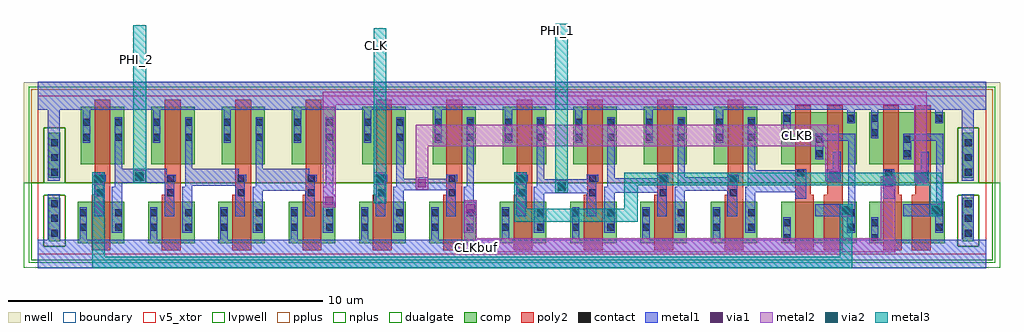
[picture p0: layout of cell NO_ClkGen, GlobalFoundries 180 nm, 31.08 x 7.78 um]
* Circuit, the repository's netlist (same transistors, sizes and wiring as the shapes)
* NGSPICE file created from NO_ClkGen.ext - technology: gf180mcuD

.subckt gf180mcu_fd_sc_mcu9t5v0__nand2_1 ZN VSS VDD A2 A1 VNW VPW
X0 ZN A2 VDD VNW pfet_05v0 ad=0.4277p pd=2.165u as=0.7238p ps=4.17u w=1.645u l=0.5u
X1 VDD A1 ZN VNW pfet_05v0 ad=0.7238p pd=4.17u as=0.4277p ps=2.165u w=1.645u l=0.5u
X2 ZN A1 a_245_69# VPW nfet_05v0 ad=0.5808p pd=3.52u as=0.2112p ps=1.64u w=1.32u l=0.6u
X3 a_245_69# A2 VSS VPW nfet_05v0 ad=0.2112p pd=1.64u as=0.5808p ps=3.52u w=1.32u l=0.6u
.ends

.subckt gf180mcu_fd_sc_mcu9t5v0__inv_1 I VDD VSS ZN VNW VPW
X0 ZN I VDD VNW pfet_05v0 ad=0.8052p pd=4.54u as=0.8052p ps=4.54u w=1.83u l=0.5u
X1 ZN I VSS VPW nfet_05v0 ad=0.5808p pd=3.52u as=0.5808p ps=3.52u w=1.32u l=0.6u
.ends

.subckt NO_ClkGen CLKB CLKbuf PHI_2 PHI_1 CLK
Xgf180mcu_fd_sc_mcu9t5v0__nand2_1_0 gf180mcu_fd_sc_mcu9t5v0__inv_1_1/I VSUBS gf180mcu_fd_sc_mcu9t5v0__inv_1_9/VNW
+ gf180mcu_fd_sc_mcu9t5v0__inv_1_0/ZN CLKB gf180mcu_fd_sc_mcu9t5v0__inv_1_9/VNW VSUBS
+ gf180mcu_fd_sc_mcu9t5v0__nand2_1
Xgf180mcu_fd_sc_mcu9t5v0__nand2_1_1 gf180mcu_fd_sc_mcu9t5v0__inv_1_7/I VSUBS gf180mcu_fd_sc_mcu9t5v0__inv_1_9/VNW
+ CLKbuf gf180mcu_fd_sc_mcu9t5v0__inv_1_4/ZN gf180mcu_fd_sc_mcu9t5v0__inv_1_9/VNW
+ VSUBS gf180mcu_fd_sc_mcu9t5v0__nand2_1
Xgf180mcu_fd_sc_mcu9t5v0__inv_1_0 gf180mcu_fd_sc_mcu9t5v0__inv_1_0/I gf180mcu_fd_sc_mcu9t5v0__inv_1_9/VNW
+ VSUBS gf180mcu_fd_sc_mcu9t5v0__inv_1_0/ZN gf180mcu_fd_sc_mcu9t5v0__inv_1_9/VNW VSUBS
+ gf180mcu_fd_sc_mcu9t5v0__inv_1
Xgf180mcu_fd_sc_mcu9t5v0__inv_1_1 gf180mcu_fd_sc_mcu9t5v0__inv_1_1/I gf180mcu_fd_sc_mcu9t5v0__inv_1_9/VNW
+ VSUBS PHI_2 gf180mcu_fd_sc_mcu9t5v0__inv_1_9/VNW VSUBS gf180mcu_fd_sc_mcu9t5v0__inv_1
Xgf180mcu_fd_sc_mcu9t5v0__inv_1_2 PHI_2 gf180mcu_fd_sc_mcu9t5v0__inv_1_9/VNW VSUBS
+ gf180mcu_fd_sc_mcu9t5v0__inv_1_3/I gf180mcu_fd_sc_mcu9t5v0__inv_1_9/VNW VSUBS gf180mcu_fd_sc_mcu9t5v0__inv_1
Xgf180mcu_fd_sc_mcu9t5v0__inv_1_3 gf180mcu_fd_sc_mcu9t5v0__inv_1_3/I gf180mcu_fd_sc_mcu9t5v0__inv_1_9/VNW
+ VSUBS gf180mcu_fd_sc_mcu9t5v0__inv_1_4/I gf180mcu_fd_sc_mcu9t5v0__inv_1_9/VNW VSUBS
+ gf180mcu_fd_sc_mcu9t5v0__inv_1
Xgf180mcu_fd_sc_mcu9t5v0__inv_1_4 gf180mcu_fd_sc_mcu9t5v0__inv_1_4/I gf180mcu_fd_sc_mcu9t5v0__inv_1_9/VNW
+ VSUBS gf180mcu_fd_sc_mcu9t5v0__inv_1_4/ZN gf180mcu_fd_sc_mcu9t5v0__inv_1_9/VNW VSUBS
+ gf180mcu_fd_sc_mcu9t5v0__inv_1
Xgf180mcu_fd_sc_mcu9t5v0__inv_1_5 CLK gf180mcu_fd_sc_mcu9t5v0__inv_1_9/VNW VSUBS CLKB
+ gf180mcu_fd_sc_mcu9t5v0__inv_1_9/VNW VSUBS gf180mcu_fd_sc_mcu9t5v0__inv_1
Xgf180mcu_fd_sc_mcu9t5v0__inv_1_6 CLKB gf180mcu_fd_sc_mcu9t5v0__inv_1_9/VNW VSUBS
+ CLKbuf gf180mcu_fd_sc_mcu9t5v0__inv_1_9/VNW VSUBS gf180mcu_fd_sc_mcu9t5v0__inv_1
Xgf180mcu_fd_sc_mcu9t5v0__inv_1_7 gf180mcu_fd_sc_mcu9t5v0__inv_1_7/I gf180mcu_fd_sc_mcu9t5v0__inv_1_9/VNW
+ VSUBS PHI_1 gf180mcu_fd_sc_mcu9t5v0__inv_1_9/VNW VSUBS gf180mcu_fd_sc_mcu9t5v0__inv_1
Xgf180mcu_fd_sc_mcu9t5v0__inv_1_8 PHI_1 gf180mcu_fd_sc_mcu9t5v0__inv_1_9/VNW VSUBS
+ gf180mcu_fd_sc_mcu9t5v0__inv_1_9/I gf180mcu_fd_sc_mcu9t5v0__inv_1_9/VNW VSUBS gf180mcu_fd_sc_mcu9t5v0__inv_1
Xgf180mcu_fd_sc_mcu9t5v0__inv_1_9 gf180mcu_fd_sc_mcu9t5v0__inv_1_9/I gf180mcu_fd_sc_mcu9t5v0__inv_1_9/VNW
+ VSUBS gf180mcu_fd_sc_mcu9t5v0__inv_1_0/I gf180mcu_fd_sc_mcu9t5v0__inv_1_9/VNW VSUBS
+ gf180mcu_fd_sc_mcu9t5v0__inv_1
.ends

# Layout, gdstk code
import gdstk
lib = gdstk.Library(unit=1e-6, precision=1e-09)
def R(c, l, rs):  # rectangles x0, y0, x1, y1
    for r in rs: c.add(gdstk.rectangle(r[:2], r[2:], *l))
def A(c, l, x, y, w, h, nx, ny, dx, dy):  # array of equal rectangles
    R(c, l, [(x+i*dx, y+j*dy, x+i*dx+w, y+j*dy+h) for i in range(nx) for j in range(ny)])
def P(c, l, *ps):  # polygons
    for p in ps: c.add(gdstk.Polygon(p, *l))
boundary = (0, 0)
nwell = (21, 0)
comp = (22, 0)
poly2 = (30, 0)
pplus = (31, 0)
nplus = (32, 0)
contact = (33, 0)
metal1 = (34, 0)
via1 = (35, 0)
metal2 = (36, 0)
via2 = (38, 0)
metal3 = (42, 0)
dualgate = (55, 0)
v5_xtor = (112, 1)
lvpwell = (204, 0)

gf180mcu_fd_sc_mcu9t5v0_ = lib.new_cell('gf180mcu_fd_sc_mcu9t5v0__inv_1')
R(gf180mcu_fd_sc_mcu9t5v0_, boundary, [(0,0,2.24,5.04)])
R(gf180mcu_fd_sc_mcu9t5v0_, nwell, [(-0.43,2.265,2.67,5.47)])
R(gf180mcu_fd_sc_mcu9t5v0_, comp, [(0.18,0.345,1.66,1.665), (0.28,2.865,1.66,4.695)])
P(gf180mcu_fd_sc_mcu9t5v0_, poly2, [(0.62,0.125),(0.62,1.885),(0.72,1.885),(0.72,4.915),(1.22,4.915),(1.22,0.125)])
R(gf180mcu_fd_sc_mcu9t5v0_, pplus, [(-0.2,2.265,2.44,5.24)])
R(gf180mcu_fd_sc_mcu9t5v0_, nplus, [(-0.2,-0.2,2.44,2.265)])
R(gf180mcu_fd_sc_mcu9t5v0_, contact, [(0.25,0.74,0.47,0.96), (1.37,0.74,1.59,0.96), (0.25,1.21,0.47,1.43), (1.37,1.21,1.59,1.43), (0.79,1.835,1.01,2.055), (0.79,2.305,1.01,2.525), (0.35,3.61,0.57,3.83), (1.37,3.61,1.59,3.83), (0.35,4.08,0.57,4.3), (1.37,4.08,1.59,4.3)])
P(gf180mcu_fd_sc_mcu9t5v0_, metal1, [(0.71,1.21),(0.71,2.53),(1.07,2.53),(1.07,2.3),(1.015,2.3),(1.015,1.21)],
  [(1.27,0.68),(1.27,2.15),(1.365,2.15),(1.365,4.36),(1.595,4.36),(1.595,0.68)],
  [(0,-0.45),(0,0.45),(0.245,0.45),(0.245,1.49),(0.475,1.49),(0.475,0.45),(2.24,0.45),(2.24,-0.45)],
  [(0.345,3.55),(0.345,4.59),(0,4.59),(0,5.49),(2.24,5.49),(2.24,4.59),(0.575,4.59),(0.575,3.55)])
R(gf180mcu_fd_sc_mcu9t5v0_, dualgate, [(-0.28,-0.28,2.52,5.32)])
R(gf180mcu_fd_sc_mcu9t5v0_, v5_xtor, [(0,0,2.24,5.04)])
R(gf180mcu_fd_sc_mcu9t5v0_, lvpwell, [(-0.43,-0.43,2.67,2.265)])
gf180mcu_fd_sc_mcu9t5v0_.add(gdstk.Label('& Vendor GLOBALFOUNDRIES', (0,2), layer=63, texttype=63))
gf180mcu_fd_sc_mcu9t5v0_.add(gdstk.Label('& Product GF018hv5v_green_sc9', (0,1.5), layer=63, texttype=63))
gf180mcu_fd_sc_mcu9t5v0_.add(gdstk.Label('& Version 2015q2v2', (0,1), layer=63, texttype=63))
gf180mcu_fd_sc_mcu9t5v0_.add(gdstk.Label('& Metric 1.00', (0,0.5), layer=63, texttype=63))
gf180mcu_fd_sc_mcu9t5v0_.add(gdstk.Label('I', (0.84,1.96), layer=34, texttype=10))
gf180mcu_fd_sc_mcu9t5v0_.add(gdstk.Label('VDD', (1.12,5.49), layer=34, texttype=10))
gf180mcu_fd_sc_mcu9t5v0_.add(gdstk.Label('VSS', (1.12,-0.45), layer=34, texttype=10))
gf180mcu_fd_sc_mcu9t5v0_.add(gdstk.Label('ZN', (1.4,1.96), layer=34, texttype=10))
gf180mcu_fd_sc_mcu9t5v0_.add(gdstk.Label('VNW', (0.345,3.92), layer=21, texttype=10))
gf180mcu_fd_sc_mcu9t5v0_.add(gdstk.Label('VPW', (0.34,-0.085), layer=204, texttype=10))

c_gf180mcu_fd_sc_mcu9t5v0_ = lib.new_cell('gf180mcu_fd_sc_mcu9t5v0__nand2_1')
R(c_gf180mcu_fd_sc_mcu9t5v0_, boundary, [(0,0,2.8,5.04)])
R(c_gf180mcu_fd_sc_mcu9t5v0_, nwell, [(-0.43,2.265,3.23,5.47)])
R(c_gf180mcu_fd_sc_mcu9t5v0_, comp, [(0.185,0.345,2.585,1.665), (0.185,2.865,2.585,4.51)])
P(c_gf180mcu_fd_sc_mcu9t5v0_, poly2, [(0.625,0.125),(0.625,4.73),(1.125,4.73),(1.125,1.885),(1.225,1.885),(1.225,0.125)],
  [(1.545,0.125),(1.545,1.885),(1.645,1.885),(1.645,4.73),(2.145,4.73),(2.145,0.125)])
R(c_gf180mcu_fd_sc_mcu9t5v0_, pplus, [(-0.2,2.265,3,5.24)])
R(c_gf180mcu_fd_sc_mcu9t5v0_, nplus, [(-0.2,-0.2,3,2.265)])
R(c_gf180mcu_fd_sc_mcu9t5v0_, contact, [(0.255,0.415,0.475,0.635), (2.295,0.74,2.515,0.96), (0.255,0.885,0.475,1.105), (2.295,1.21,2.515,1.43), (1.835,2.39,2.055,2.61), (0.695,2.475,0.915,2.695), (1.275,3.08,1.495,3.3), (1.275,3.55,1.495,3.77), (0.255,3.75,0.475,3.97), (0.255,4.22,0.475,4.44), (2.295,4.22,2.515,4.44)])
R(c_gf180mcu_fd_sc_mcu9t5v0_, metal1, [(0.635,1.76,0.975,2.7), (1.825,2.315,2.085,3.255)])
P(c_gf180mcu_fd_sc_mcu9t5v0_, metal1, [(2.285,0.68),(2.285,1.21),(1.265,1.21),(1.265,1.59),(2.315,1.59),(2.315,3.6),(1.525,3.6),(1.525,3.02),(1.265,3.02),(1.265,3.83),(2.545,3.83),(2.545,0.68)],
  [(0.25,3.69),(0.25,4.59),(0,4.59),(0,5.49),(2.8,5.49),(2.8,4.59),(2.52,4.59),(2.52,4.16),(2.29,4.16),(2.29,4.59),(0.48,4.59),(0.48,3.69)],
  [(0,-0.45),(0,0.45),(0.25,0.45),(0.25,1.165),(0.48,1.165),(0.48,0.45),(2.8,0.45),(2.8,-0.45)])
R(c_gf180mcu_fd_sc_mcu9t5v0_, dualgate, [(-0.28,-0.28,3.08,5.32)])
R(c_gf180mcu_fd_sc_mcu9t5v0_, v5_xtor, [(0,0,2.8,5.04)])
R(c_gf180mcu_fd_sc_mcu9t5v0_, lvpwell, [(-0.43,-0.43,3.23,2.265)])
c_gf180mcu_fd_sc_mcu9t5v0_.add(gdstk.Label('& Vendor GLOBALFOUNDRIES', (0,2), layer=63, texttype=63))
c_gf180mcu_fd_sc_mcu9t5v0_.add(gdstk.Label('& Product GF018hv5v_green_sc9', (0,1.5), layer=63, texttype=63))
c_gf180mcu_fd_sc_mcu9t5v0_.add(gdstk.Label('& Version 2015q2v2', (0,1), layer=63, texttype=63))
c_gf180mcu_fd_sc_mcu9t5v0_.add(gdstk.Label('& Metric 1.00', (0,0.5), layer=63, texttype=63))
c_gf180mcu_fd_sc_mcu9t5v0_.add(gdstk.Label('ZN', (1.96,1.4), layer=34, texttype=10))
c_gf180mcu_fd_sc_mcu9t5v0_.add(gdstk.Label('VSS', (1.4,-0.45), layer=34, texttype=10))
c_gf180mcu_fd_sc_mcu9t5v0_.add(gdstk.Label('VDD', (1.4,5.49), layer=34, texttype=10))
c_gf180mcu_fd_sc_mcu9t5v0_.add(gdstk.Label('A2', (0.84,1.96), layer=34, texttype=10))
c_gf180mcu_fd_sc_mcu9t5v0_.add(gdstk.Label('A1', (1.96,2.52), layer=34, texttype=10))
c_gf180mcu_fd_sc_mcu9t5v0_.add(gdstk.Label('VNW', (0.345,3.92), layer=21, texttype=10))
c_gf180mcu_fd_sc_mcu9t5v0_.add(gdstk.Label('VPW', (0.34,-0.085), layer=204, texttype=10))

c_gf180mcu_fd_sc_mcu9t5v0__ = lib.new_cell('gf180mcu_fd_sc_mcu9t5v0__filltie')
R(c_gf180mcu_fd_sc_mcu9t5v0__, boundary, [(0,0,1.12,5.04)])
R(c_gf180mcu_fd_sc_mcu9t5v0__, nwell, [(-0.43,2.265,1.55,5.47)])
R(c_gf180mcu_fd_sc_mcu9t5v0__, comp, [(0.36,0.41,0.72,1.785), (0.36,2.425,0.72,3.855)])
R(c_gf180mcu_fd_sc_mcu9t5v0__, pplus, [(0.2,0.25,0.88,1.865)])
P(c_gf180mcu_fd_sc_mcu9t5v0__, pplus, [(-0.2,2.265),(-0.2,5.24),(1.32,5.24),(1.32,2.265),(0.88,2.265),(0.88,4.015),(0.2,4.015),(0.2,2.265)])
P(c_gf180mcu_fd_sc_mcu9t5v0__, nplus, [(-0.2,-0.2),(-0.2,2.265),(0.2,2.265),(0.2,4.015),(0.88,4.015),(0.88,1.865),(0.2,1.865),(0.2,0.25),(0.88,0.25),(0.88,4.015),(0.88,2.265),(1.32,2.265),(1.32,-0.2)])
A(c_gf180mcu_fd_sc_mcu9t5v0__, contact, 0.43, 0.555, 0.22, 0.22, 1, 3, 0, 0.47)
A(c_gf180mcu_fd_sc_mcu9t5v0__, contact, 0.43, 2.495, 0.22, 0.22, 1, 3, 0, 0.47)
P(c_gf180mcu_fd_sc_mcu9t5v0__, metal1, [(0,-0.45),(0,0.45),(0.33,0.45),(0.33,1.91),(0.71,1.91),(0.71,0.45),(1.12,0.45),(1.12,-0.45)],
  [(0.33,2.34),(0.33,4.59),(0,4.59),(0,5.49),(1.12,5.49),(1.12,4.59),(0.71,4.59),(0.71,2.34)])
R(c_gf180mcu_fd_sc_mcu9t5v0__, dualgate, [(-0.28,-0.28,1.4,5.32)])
R(c_gf180mcu_fd_sc_mcu9t5v0__, v5_xtor, [(0,0,1.12,5.04)])
R(c_gf180mcu_fd_sc_mcu9t5v0__, lvpwell, [(-0.43,-0.43,1.55,2.265)])
c_gf180mcu_fd_sc_mcu9t5v0__.add(gdstk.Label('& Vendor GLOBALFOUNDRIES', (0,2), layer=63, texttype=63))
c_gf180mcu_fd_sc_mcu9t5v0__.add(gdstk.Label('& Product GF018hv5v_green_sc9', (0,1.5), layer=63, texttype=63))
c_gf180mcu_fd_sc_mcu9t5v0__.add(gdstk.Label('& Version 2015q2v2', (0,1), layer=63, texttype=63))
c_gf180mcu_fd_sc_mcu9t5v0__.add(gdstk.Label('& Metric 1.00', (0,0.5), layer=63, texttype=63))
c_gf180mcu_fd_sc_mcu9t5v0__.add(gdstk.Label('VSS', (0.56,-0.45), layer=34, texttype=10))
c_gf180mcu_fd_sc_mcu9t5v0__.add(gdstk.Label('VDD', (0.56,5.49), layer=34, texttype=10))

via_dev = lib.new_cell('via_dev')
R(via_dev, metal1, [(0,0,0.4,0.4)])
R(via_dev, via1, [(0.07,0.07,0.33,0.33)])
R(via_dev, metal2, [(0,0,0.4,0.4)])

via_dev_1 = lib.new_cell('via_dev$1')
R(via_dev_1, metal1, [(0,0,0.4,0.4)])
R(via_dev_1, via1, [(0.07,0.07,0.33,0.33)])
R(via_dev_1, metal2, [(0,0,0.4,0.4)])
R(via_dev_1, via2, [(0.07,0.07,0.33,0.33)])
R(via_dev_1, metal3, [(0,0,0.4,0.4)])

no_clkgen = lib.new_cell('NO_ClkGen')
R(no_clkgen, metal1, [(15.05,1.93,16.65,2.38), (17.27,1.95,18.88,2.41), (21.74,1.96,23.26,2.66), (6.165,2.01,7.64,2.72), (19.51,2.01,21.09,2.44), (10.51,2.03,12.1,2.4), (3.83,2.17,5.4,2.71), (1.59,2.27,3.11,2.71)])
P(no_clkgen, metal2, [(11.03,2.05),(11.03,4.12),(24.51,4.12),(24.51,2.315),(24.07,2.315),(24.07,3.43),(11.43,3.43),(11.43,2.05)],
  [(12.58,0.06),(12.58,1.71),(12.98,1.71),(12.98,0.51),(25.85,0.51),(25.85,2.48),(26.31,2.48),(26.31,0.06)],
  [(8.08,1.49),(8.08,5.16),(27.31,5.16),(27.31,2.25),(26.91,2.25),(26.91,4.76),(8.48,4.76),(8.48,1.49)])
R(no_clkgen, metal3, [(9.7,1.62,10.1,7.19), (15.48,1.95,15.88,7.33), (2.04,2.27,2.46,7.29)])
P(no_clkgen, metal3, [(14.17,1.03),(14.17,2.6),(14.57,2.6),(14.57,1.44),(17.67,1.44),(17.67,2.59),(27.79,2.59),(27.79,1.2),(27.39,1.2),(27.39,2.19),(18.11,2.19),(18.11,1.03)],
  [(0.73,-0.45),(0.73,2.6),(1.13,2.6),(1.13,-0.09),(24.54,-0.09),(24.54,1.59),(24.94,1.59),(24.94,-0.45)])
no_clkgen.add(gdstk.Reference(gf180mcu_fd_sc_mcu9t5v0_, (18.01,0)))
no_clkgen.add(gdstk.Reference(gf180mcu_fd_sc_mcu9t5v0_, (15.77,0)))
no_clkgen.add(gdstk.Reference(gf180mcu_fd_sc_mcu9t5v0_, (13.53,0)))
no_clkgen.add(gdstk.Reference(gf180mcu_fd_sc_mcu9t5v0_, (11.29,0)))
no_clkgen.add(gdstk.Reference(gf180mcu_fd_sc_mcu9t5v0_, (9.05,0)))
no_clkgen.add(gdstk.Reference(gf180mcu_fd_sc_mcu9t5v0_, (6.81,0)))
no_clkgen.add(gdstk.Reference(gf180mcu_fd_sc_mcu9t5v0_, (4.57,0)))
no_clkgen.add(gdstk.Reference(gf180mcu_fd_sc_mcu9t5v0_, (2.33,0)))
no_clkgen.add(gdstk.Reference(gf180mcu_fd_sc_mcu9t5v0_, (0.09,0)))
no_clkgen.add(gdstk.Reference(gf180mcu_fd_sc_mcu9t5v0_, (20.25,0)))
no_clkgen.add(gdstk.Reference(c_gf180mcu_fd_sc_mcu9t5v0_, (25.29,0)))
no_clkgen.add(gdstk.Reference(c_gf180mcu_fd_sc_mcu9t5v0_, (22.49,0)))
no_clkgen.add(gdstk.Reference(c_gf180mcu_fd_sc_mcu9t5v0__, (-1.01,0)))
no_clkgen.add(gdstk.Reference(c_gf180mcu_fd_sc_mcu9t5v0__, (28.09,0)))
no_clkgen.add(gdstk.Reference(via_dev, (24.13,2.3)))
no_clkgen.add(gdstk.Reference(via_dev, (25.91,2.08)))
no_clkgen.add(gdstk.Reference(via_dev_1, (15.48,1.95)))
no_clkgen.add(gdstk.Reference(via_dev, (11.03,2.05)))
no_clkgen.add(gdstk.Reference(via_dev_1, (2.04,2.27)))
no_clkgen.add(gdstk.Reference(via_dev, (8.08,1.49)))
no_clkgen.add(gdstk.Reference(via_dev_1, (24.54,1.19)))
no_clkgen.add(gdstk.Reference(via_dev_1, (27.39,1.2)))
no_clkgen.add(gdstk.Reference(via_dev_1, (9.69,2.2)))
no_clkgen.add(gdstk.Reference(via_dev, (12.58,1.26)))
no_clkgen.add(gdstk.Reference(via_dev_1, (0.73,2.2)))
no_clkgen.add(gdstk.Reference(via_dev_1, (14.17,2.2)))
no_clkgen.add(gdstk.Reference(via_dev, (26.91,2.25)))
no_clkgen.add(gdstk.Label('CLKB', (23.18,3.76), layer=36, texttype=10))
no_clkgen.add(gdstk.Label('CLKbuf', (12.97,0.2), layer=36, texttype=10))
no_clkgen.add(gdstk.Label('PHI_2', (2.15,6.21), layer=42, texttype=10))
no_clkgen.add(gdstk.Label('PHI_1', (15.56,7.12), layer=42, texttype=10))
no_clkgen.add(gdstk.Label('CLK', (9.77,6.63), layer=42, texttype=10))

lib.write_gds('NO_ClkGen.gds')
